One B-rep face of a CAD part: STEP entity #39.
In plain terms, the planar face has unit normal (-1, 0, 0).
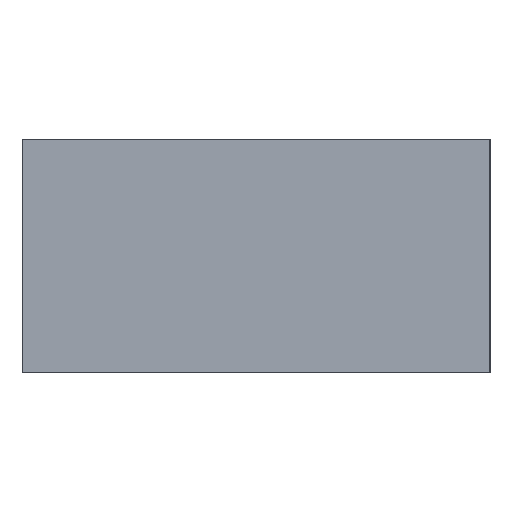
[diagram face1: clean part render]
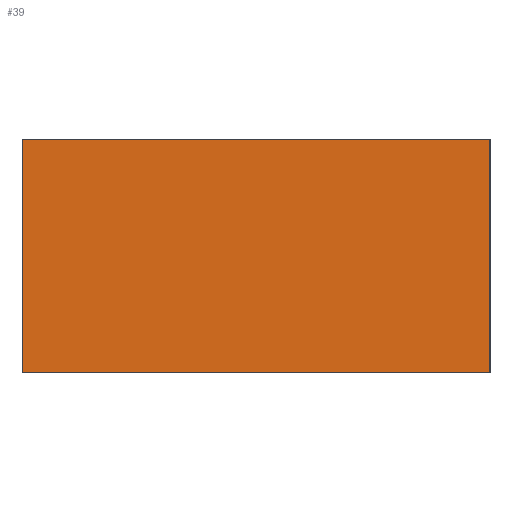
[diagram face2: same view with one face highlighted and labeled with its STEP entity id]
Its self-contained STEP definition (entity closure, numbers rounded to 3 decimals):
#39 = ADVANCED_FACE('',(#40),#54,.F.);
#40 = FACE_BOUND('',#41,.F.);
#41 = EDGE_LOOP('',(#42,#77,#105,#133));
#42 = ORIENTED_EDGE('',*,*,#43,.F.);
#43 = EDGE_CURVE('',#44,#46,#48,.T.);
#44 = VERTEX_POINT('',#45);
#45 = CARTESIAN_POINT('',(0.,0.,0.));
#46 = VERTEX_POINT('',#47);
#47 = CARTESIAN_POINT('',(0.,0.,4.));
#48 = SURFACE_CURVE('',#49,(#53,#65),.PCURVE_S1.);
#49 = LINE('',#50,#51);
#50 = CARTESIAN_POINT('',(0.,0.,0.));
#51 = VECTOR('',#52,1.);
#52 = DIRECTION('',(0.,0.,1.));
#53 = PCURVE('',#54,#59);
#54 = PLANE('',#55);
#55 = AXIS2_PLACEMENT_3D('',#56,#57,#58);
#56 = CARTESIAN_POINT('',(0.,0.,0.));
#57 = DIRECTION('',(1.,0.,0.));
#58 = DIRECTION('',(0.,0.,1.));
#59 = DEFINITIONAL_REPRESENTATION('',(#60),#64);
#60 = LINE('',#61,#62);
#61 = CARTESIAN_POINT('',(0.,0.));
#62 = VECTOR('',#63,1.);
#63 = DIRECTION('',(1.,0.));
#64 = ( GEOMETRIC_REPRESENTATION_CONTEXT(2) 
PARAMETRIC_REPRESENTATION_CONTEXT() REPRESENTATION_CONTEXT('2D SPACE',''
  ) );
#65 = PCURVE('',#66,#71);
#66 = PLANE('',#67);
#67 = AXIS2_PLACEMENT_3D('',#68,#69,#70);
#68 = CARTESIAN_POINT('',(0.,0.,0.));
#69 = DIRECTION('',(0.,1.,0.));
#70 = DIRECTION('',(0.,0.,1.));
#71 = DEFINITIONAL_REPRESENTATION('',(#72),#76);
#72 = LINE('',#73,#74);
#73 = CARTESIAN_POINT('',(0.,0.));
#74 = VECTOR('',#75,1.);
#75 = DIRECTION('',(1.,0.));
#76 = ( GEOMETRIC_REPRESENTATION_CONTEXT(2) 
PARAMETRIC_REPRESENTATION_CONTEXT() REPRESENTATION_CONTEXT('2D SPACE',''
  ) );
#77 = ORIENTED_EDGE('',*,*,#78,.T.);
#78 = EDGE_CURVE('',#44,#79,#81,.T.);
#79 = VERTEX_POINT('',#80);
#80 = CARTESIAN_POINT('',(0.,8.,0.));
#81 = SURFACE_CURVE('',#82,(#86,#93),.PCURVE_S1.);
#82 = LINE('',#83,#84);
#83 = CARTESIAN_POINT('',(0.,0.,0.));
#84 = VECTOR('',#85,1.);
#85 = DIRECTION('',(0.,1.,0.));
#86 = PCURVE('',#54,#87);
#87 = DEFINITIONAL_REPRESENTATION('',(#88),#92);
#88 = LINE('',#89,#90);
#89 = CARTESIAN_POINT('',(0.,0.));
#90 = VECTOR('',#91,1.);
#91 = DIRECTION('',(0.,-1.));
#92 = ( GEOMETRIC_REPRESENTATION_CONTEXT(2) 
PARAMETRIC_REPRESENTATION_CONTEXT() REPRESENTATION_CONTEXT('2D SPACE',''
  ) );
#93 = PCURVE('',#94,#99);
#94 = PLANE('',#95);
#95 = AXIS2_PLACEMENT_3D('',#96,#97,#98);
#96 = CARTESIAN_POINT('',(0.,0.,0.));
#97 = DIRECTION('',(0.,0.,1.));
#98 = DIRECTION('',(1.,0.,0.));
#99 = DEFINITIONAL_REPRESENTATION('',(#100),#104);
#100 = LINE('',#101,#102);
#101 = CARTESIAN_POINT('',(0.,0.));
#102 = VECTOR('',#103,1.);
#103 = DIRECTION('',(0.,1.));
#104 = ( GEOMETRIC_REPRESENTATION_CONTEXT(2) 
PARAMETRIC_REPRESENTATION_CONTEXT() REPRESENTATION_CONTEXT('2D SPACE',''
  ) );
#105 = ORIENTED_EDGE('',*,*,#106,.T.);
#106 = EDGE_CURVE('',#79,#107,#109,.T.);
#107 = VERTEX_POINT('',#108);
#108 = CARTESIAN_POINT('',(0.,8.,4.));
#109 = SURFACE_CURVE('',#110,(#114,#121),.PCURVE_S1.);
#110 = LINE('',#111,#112);
#111 = CARTESIAN_POINT('',(0.,8.,0.));
#112 = VECTOR('',#113,1.);
#113 = DIRECTION('',(0.,0.,1.));
#114 = PCURVE('',#54,#115);
#115 = DEFINITIONAL_REPRESENTATION('',(#116),#120);
#116 = LINE('',#117,#118);
#117 = CARTESIAN_POINT('',(0.,-8.));
#118 = VECTOR('',#119,1.);
#119 = DIRECTION('',(1.,0.));
#120 = ( GEOMETRIC_REPRESENTATION_CONTEXT(2) 
PARAMETRIC_REPRESENTATION_CONTEXT() REPRESENTATION_CONTEXT('2D SPACE',''
  ) );
#121 = PCURVE('',#122,#127);
#122 = PLANE('',#123);
#123 = AXIS2_PLACEMENT_3D('',#124,#125,#126);
#124 = CARTESIAN_POINT('',(0.,8.,0.));
#125 = DIRECTION('',(0.,1.,0.));
#126 = DIRECTION('',(0.,0.,1.));
#127 = DEFINITIONAL_REPRESENTATION('',(#128),#132);
#128 = LINE('',#129,#130);
#129 = CARTESIAN_POINT('',(0.,0.));
#130 = VECTOR('',#131,1.);
#131 = DIRECTION('',(1.,0.));
#132 = ( GEOMETRIC_REPRESENTATION_CONTEXT(2) 
PARAMETRIC_REPRESENTATION_CONTEXT() REPRESENTATION_CONTEXT('2D SPACE',''
  ) );
#133 = ORIENTED_EDGE('',*,*,#134,.F.);
#134 = EDGE_CURVE('',#46,#107,#135,.T.);
#135 = SURFACE_CURVE('',#136,(#140,#147),.PCURVE_S1.);
#136 = LINE('',#137,#138);
#137 = CARTESIAN_POINT('',(0.,0.,4.));
#138 = VECTOR('',#139,1.);
#139 = DIRECTION('',(0.,1.,0.));
#140 = PCURVE('',#54,#141);
#141 = DEFINITIONAL_REPRESENTATION('',(#142),#146);
#142 = LINE('',#143,#144);
#143 = CARTESIAN_POINT('',(4.,0.));
#144 = VECTOR('',#145,1.);
#145 = DIRECTION('',(0.,-1.));
#146 = ( GEOMETRIC_REPRESENTATION_CONTEXT(2) 
PARAMETRIC_REPRESENTATION_CONTEXT() REPRESENTATION_CONTEXT('2D SPACE',''
  ) );
#147 = PCURVE('',#148,#153);
#148 = PLANE('',#149);
#149 = AXIS2_PLACEMENT_3D('',#150,#151,#152);
#150 = CARTESIAN_POINT('',(0.,0.,4.));
#151 = DIRECTION('',(0.,0.,1.));
#152 = DIRECTION('',(1.,0.,0.));
#153 = DEFINITIONAL_REPRESENTATION('',(#154),#158);
#154 = LINE('',#155,#156);
#155 = CARTESIAN_POINT('',(0.,0.));
#156 = VECTOR('',#157,1.);
#157 = DIRECTION('',(0.,1.));
#158 = ( GEOMETRIC_REPRESENTATION_CONTEXT(2) 
PARAMETRIC_REPRESENTATION_CONTEXT() REPRESENTATION_CONTEXT('2D SPACE',''
  ) );
